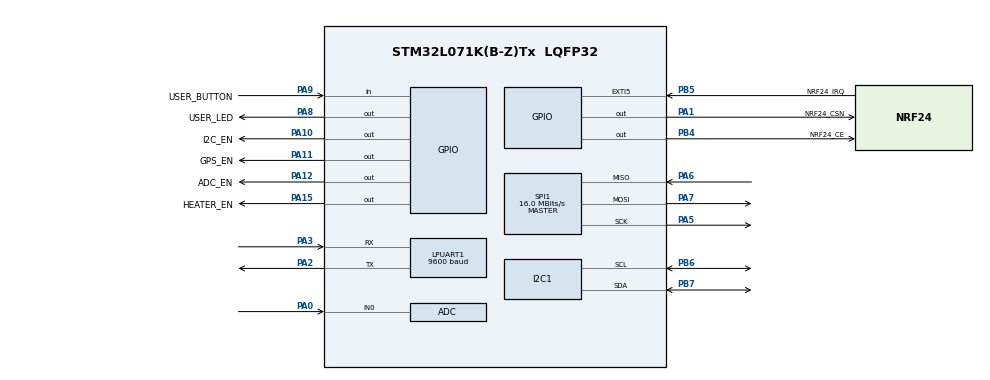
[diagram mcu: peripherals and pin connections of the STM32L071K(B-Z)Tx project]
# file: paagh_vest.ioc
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ADC.ContinuousConvMode=ENABLE
ADC.DMAContinuousRequests=ENABLE
ADC.SamplingTime=ADC_SAMPLETIME_160CYCLES_5
Dma.ADC.0.Direction=DMA_PERIPH_TO_MEMORY
Dma.ADC.0.Instance=DMA1_Channel1
Dma.ADC.0.MemDataAlignment=DMA_MDATAALIGN_WORD
Dma.ADC.0.MemInc=DMA_MINC_ENABLE
Dma.ADC.0.Mode=DMA_CIRCULAR
Dma.ADC.0.PeriphDataAlignment=DMA_PDATAALIGN_WORD
Dma.ADC.0.PeriphInc=DMA_PINC_DISABLE
Dma.ADC.0.Priority=DMA_PRIORITY_LOW
Dma.Request0=ADC
I2C1.Timing=0x00707CBB
LPUART1.BaudRate=9600
LPUART1.WordLength=UART_WORDLENGTH_8B
Mcu.Family=STM32L0
Mcu.Name=STM32L071K(B-Z)Tx
Mcu.Package=LQFP32
NVIC.DMA1_Channel1_IRQn=true\:0\:0\:false\:false\:true\:false\:true\:true
NVIC.EXTI4_15_IRQn=true\:0\:0\:false\:false\:true\:true\:true\:true
NVIC.LPUART1_IRQn=true\:0\:0\:false\:false\:true\:true\:true\:true
NVIC.TIM6_IRQn=true\:0\:0\:false\:false\:true\:true\:true\:true
PA0.Mode=IN0
PA0.Signal=ADC_IN0
PA1.GPIO_Label=NRF24_CSN
PA1.Signal=GPIO_Output
PA10.GPIO_Label=I2C_EN
PA10.Signal=GPIO_Output
PA11.GPIO_Label=GPS_EN
PA11.Signal=GPIO_Output
PA12.GPIO_Label=ADC_EN
PA12.Signal=GPIO_Output
PA13.Mode=Serial_Wire
PA13.Signal=SYS_SWDIO
PA14.Mode=Serial_Wire
PA14.Signal=SYS_SWCLK
PA15.GPIO_Label=HEATER_EN
PA15.Signal=GPIO_Output
PA2.Mode=Asynchronous
PA2.Signal=LPUART1_TX
PA3.Mode=Asynchronous
PA3.Signal=LPUART1_RX
PA5.Mode=Full_Duplex_Master
PA5.Signal=SPI1_SCK
PA6.Mode=Full_Duplex_Master
PA6.Signal=SPI1_MISO
PA7.Mode=Full_Duplex_Master
PA7.Signal=SPI1_MOSI
PA8.GPIO_Label=USER_LED
PA8.Signal=GPIO_Output
PA9.GPIO_Label=USER_BUTTON
PA9.Signal=GPIO_Input
PB4.GPIO_Label=NRF24_CE
PB4.Signal=GPIO_Output
PB5.GPIO_Label=NRF24_IRQ
PB5.Signal=GPXTI5
PB6.Mode=I2C
PB6.Signal=I2C1_SCL
PB7.Mode=I2C
PB7.Signal=I2C1_SDA
ProjectManager.HeapSize=0x200
ProjectManager.StackSize=0x400
ProjectManager.TargetToolchain=Makefile
RCC.AHBFreq_Value=32000000
RCC.APB1Freq_Value=32000000
RCC.APB1TimFreq_Value=32000000
RCC.APB2Freq_Value=32000000
RCC.APB2TimFreq_Value=32000000
RCC.HCLKFreq_Value=32000000
RCC.HSI16_VALUE=16000000
RCC.HSI_VALUE=16000000
RCC.LSE_VALUE=32768
RCC.MSI_VALUE=2097000
RCC.PLLMUL=RCC_PLLMUL_4
RCC.SYSCLKFreq_VALUE=32000000
RCC.SYSCLKSource=RCC_SYSCLKSOURCE_PLLCLK
RCC.VCOOutputFreq_Value=64000000
SPI1.CalculateBaudRate=16.0 MBits/s
SPI1.Direction=SPI_DIRECTION_2LINES
SPI1.Mode=SPI_MODE_MASTER
SPI1.VirtualType=VM_MASTER
TIM6.Period=9999
TIM6.Prescaler=3199
VP_TIM6_VS_ClockSourceINT.Mode=Enable_Timer
board=custom

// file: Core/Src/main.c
/* USER CODE BEGIN Header */
/**
  ******************************************************************************
  * @file           : main.c
  * @brief          : Main program body
  ******************************************************************************
  * @attention
  *
  * Copyright (c) 2024 STMicroelectronics.
  * All rights reserved.
  *
  * This software is licensed under terms that can be found in the LICENSE file
  * in the root directory of this software component.
  * If no LICENSE file comes with this software, it is provided AS-IS.
  *
  ******************************************************************************
  */
/* USER CODE END Header */
#include "main.h"
#include "adc.h"
#include "dma.h"
#include "i2c.h"
#include "usart.h"
#include "spi.h"
#include "tim.h"
#include "gpio.h"

/* USER CODE BEGIN Includes */

#include <string.h>
#include <stdio.h>
#include <stdbool.h>
#include "AHT20.h"
#include "NEO6.h"
#include <nRF24.h>
#include "pv_app.h"
#include "pv_pulse.h"

// #include <debug.h>

/* USER CODE END Includes */

void SystemClock_Config(void);

/* USER CODE BEGIN 0 */

NEO6_State GpsState;

volatile uint32_t HeartBeatValue;
volatile uint32_t HeartBeatArray[HEART_BEAT_ARRAY_SIZE] = {0};
volatile uint8_t HeartBeatIndex = 0;

void HAL_UART_RxCpltCallback(UART_HandleTypeDef *huart)
{
  if(huart == GpsState.neo6_huart)
  {
    NEO6_ReceiveUartChar(&GpsState);
  }
}

void HAL_TIM_PeriodElapsedCallback(TIM_HandleTypeDef *htim)
{
  if (htim == &htim6)
  {
  }
}

void HAL_ADC_ConvCpltCallback(ADC_HandleTypeDef* hadc)
{
	if(HeartBeatIndex > HEART_BEAT_ARRAY_SIZE)
	{
		HeartBeatIndex = 0;
	}
	HeartBeatArray[HeartBeatIndex] = HeartBeatValue;
	HeartBeatIndex++;
}

/* USER CODE END 0 */

int main(void)
{

  /* MCU Configuration--------------------------------------------------------*/

  /* Reset of all peripherals, Initializes the Flash interface and the Systick. */
  HAL_Init();

  /* Configure the system clock */
  SystemClock_Config();

  /* Initialize all configured peripherals */
  MX_GPIO_Init();
  MX_DMA_Init();
  MX_ADC_Init();
  MX_I2C1_Init();
  MX_LPUART1_UART_Init();
  MX_SPI1_Init();
  MX_TIM6_Init();

  /* Infinite loop */
  /* USER CODE BEGIN WHILE */

  HAL_TIM_Base_Start_IT(&htim6);
  HAL_ADCEx_Calibration_Start(&hadc, ADC_SINGLE_ENDED);
  HAL_ADC_Start_DMA(&hadc, &HeartBeatValue, 2);

  while (1)
  {

    /* USER CODE END WHILE */

    /* USER CODE BEGIN 3 */

	 pv_run();

  }
  /* USER CODE END 3 */
}

void SystemClock_Config(void)
{
  RCC_OscInitTypeDef RCC_OscInitStruct = {0};
  RCC_ClkInitTypeDef RCC_ClkInitStruct = {0};
  RCC_PeriphCLKInitTypeDef PeriphClkInit = {0};

  /** Configure the main internal regulator output voltage
  */
  __HAL_PWR_VOLTAGESCALING_CONFIG(PWR_REGULATOR_VOLTAGE_SCALE1);

  /** Initializes the RCC Oscillators according to the specified parameters
  * in the RCC_OscInitTypeDef structure.
  */
  RCC_OscInitStruct.OscillatorType = RCC_OSCILLATORTYPE_HSI;
  RCC_OscInitStruct.HSIState = RCC_HSI_ON;
  RCC_OscInitStruct.HSICalibrationValue = RCC_HSICALIBRATION_DEFAULT;
  RCC_OscInitStruct.PLL.PLLState = RCC_PLL_ON;
  RCC_OscInitStruct.PLL.PLLSource = RCC_PLLSOURCE_HSI;
  RCC_OscInitStruct.PLL.PLLMUL = RCC_PLLMUL_3;
  RCC_OscInitStruct.PLL.PLLDIV = RCC_PLLDIV_3;
  if (HAL_RCC_OscConfig(&RCC_OscInitStruct) != HAL_OK)
  {
    Error_Handler();
  }

  /** Initializes the CPU, AHB and APB buses clocks
  */
  RCC_ClkInitStruct.ClockType = RCC_CLOCKTYPE_HCLK|RCC_CLOCKTYPE_SYSCLK
                              |RCC_CLOCKTYPE_PCLK1|RCC_CLOCKTYPE_PCLK2;
  RCC_ClkInitStruct.SYSCLKSource = RCC_SYSCLKSOURCE_PLLCLK;
  RCC_ClkInitStruct.AHBCLKDivider = RCC_SYSCLK_DIV16;
  RCC_ClkInitStruct.APB1CLKDivider = RCC_HCLK_DIV1;
  RCC_ClkInitStruct.APB2CLKDivider = RCC_HCLK_DIV1;

  if (HAL_RCC_ClockConfig(&RCC_ClkInitStruct, FLASH_LATENCY_0) != HAL_OK)
  {
    Error_Handler();
  }
  PeriphClkInit.PeriphClockSelection = RCC_PERIPHCLK_LPUART1|RCC_PERIPHCLK_I2C1;
  PeriphClkInit.Lpuart1ClockSelection = RCC_LPUART1CLKSOURCE_PCLK1;
  PeriphClkInit.I2c1ClockSelection = RCC_I2C1CLKSOURCE_PCLK1;
  if (HAL_RCCEx_PeriphCLKConfig(&PeriphClkInit) != HAL_OK)
  {
    Error_Handler();
  }
}

void Error_Handler(void)
{
  __disable_irq();
  while (1)
  {
  }
}
